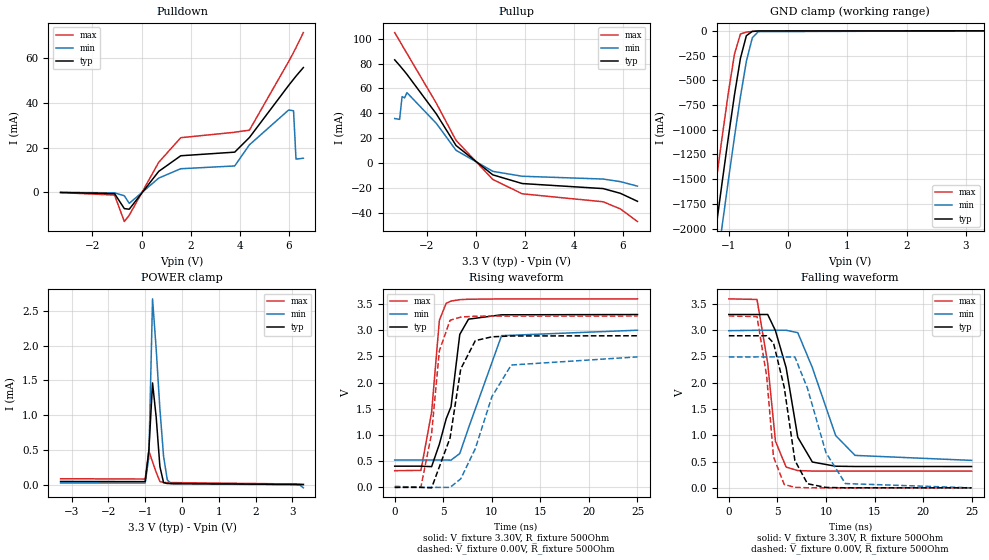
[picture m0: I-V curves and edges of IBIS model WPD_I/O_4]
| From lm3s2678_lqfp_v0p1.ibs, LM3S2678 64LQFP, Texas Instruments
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[Model]   WPD_I/O_4
Model_type   I/O
Vinl = 1.26
Vinh = 2.04
Vmeas = 1.65
| variable   typ   min   max
C_comp   9.739pF   9.739pF   9.803pF
[Model Spec]
Vinh+   1.91   1.78   2.04
Vinh-   1.90   1.76   2.03
Vinl+   1.40   1.27   1.54
Vinl-   1.39   1.26   1.53
| variable   typ   min   max
[Temperature Range]  25   85   -40
[Voltage Range]   3.3V   3.0V   3.6V
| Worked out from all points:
|   slope of the pulldown table from 0 to 0.495 V, typ, clamps not added: 71.6 ohm
|   slope of the pullup table from 0 to 0.495 V, typ, clamps not added: 71.6 ohm
|   GND clamp passes 1 mA (typ) near -0.48 V on its own axis
|   POWER clamp passes 1 mA (typ) near -0.71 V on its own axis
|   falling waveform, V_fixture 3.30V, R_fixture 500Ohm: 20-80 % time 1.98ns typ, 2.95ns min, 1.33ns max; typ from 3.3 V to 0.405 V
|   rising waveform, V_fixture 3.30V, R_fixture 500Ohm: 20-80 % time 1.71ns typ, 2.4ns min, 1.18ns max; typ from 0.405 V to 3.3 V
|   falling waveform, V_fixture 0.00V, R_fixture 500Ohm: 20-80 % time 1.7ns typ, 2.49ns min, 1.18ns max; typ from 2.89 V to 0 V
|   rising waveform, V_fixture 0.00V, R_fixture 500Ohm: 20-80 % time 2.03ns typ, 3.15ns min, 1.33ns max; typ from 0 V to 2.89 V
[Pulldown]
|  Voltage   I(typ)   I(min)   I(max)
-3.3V     -128.2uA   -72.79uA   -182.2uA
-1.1V     -636.2uA   -293.6uA   -1.283mA
-700mV    -7.354mA   -1.607mA   -13.15mA
-500mV    -7.623mA   -4.999mA   -10.32mA
700mV     9.301mA    6.299mA    13.36mA
1.6V      16.31mA    10.5mA     24.39mA
3.8V      17.93mA    11.75mA    26.84mA
4.4V      24.48mA    21.2mA     27.77mA
6V        47.8mA     36.79mA    58.49mA
6.2V      50.58mA    36.45mA    62.56mA
6.3V      51.96mA    14.82mA    64.7mA
6.6V      55.8mA     15.2mA     71.46mA
[Pullup]
|  Voltage   I(typ)   I(min)   I(max)
-3.3V     82.93mA    35.9mA     104.8mA
-3.1V     78.45mA    35.22mA    98.08mA
-3V       76.11mA    53.48mA    94.72mA
-2.9V     73.72mA    52.42mA    91.37mA
-2.8V     71.3mA     56.63mA    88.02mA
-1.6V     39.54mA    31.95mA    48.05mA
-800mV    14.3mA     10.46mA    18.4mA
700mV     -9.236mA   -6.432mA   -12.93mA
1.9V      -16.21mA   -10.36mA   -24.42mA
5.2V      -20.25mA   -12.6mA    -30.83mA
5.9V      -24.02mA   -14.69mA   -36.53mA
6.6V      -30.45mA   -18.28mA   -46.68mA
[GND Clamp]
|  Voltage   I(typ)   I(min)   I(max)
-3.3V     -11.73A    -12.14A    -11.32A
-1.4V     -2.85A     -3.29A     -2.391A
-1.3V     -2.393A    -2.835A    -1.933A
-1.2V     -1.942A    -2.383A    -1.481A
-1.1V     -1.496A    -1.937A    -1.038A
-1V       -1.061A    -1.498A    -612.1mA
-900mV    -646.5mA   -1.071A    -233.9mA
-800mV    -278.2mA   -665.9mA   -32.18mA
-700mV    -49.13mA   -307.7mA   -12.5mA
-600mV    -5.766mA   -70.86mA   -6.513mA
-500mV    -1.212mA   -8.171mA   -2.264mA
3.3V      16.11uA    11.95uA    29.77uA
[POWER Clamp]
|  Voltage   I(typ)   I(min)   I(max)
-3.3V     45.95uA    24.7uA     84.99uA
-1V       43.79uA    23.54uA    81.02uA
-900mV    497uA      400.5uA    481.3uA
-800mV    1.464mA    2.675mA    328uA
-700mV    965.7uA    1.944mA    175.8uA
-600mV    259.3uA    1.087mA    45.21uA
-500mV    29.01uA    407.8uA    31.06uA
-400mV    16.44uA    70.61uA    29.85uA
-300mV    16.12uA    11.95uA    29.79uA
3.1V      2.407uA    -925.9nA   9.193uA
3.2V      1.227uA    -4.064uA   7.471uA
3.3V      -117.9pA   -46.06uA   5.69uA
[Ramp]
| variable   typ   min   max
dV/dt_f   1.73/1.98n   1.48/2.95n   1.97/1.33n
dV/dt_r   1.74/2.03n   1.48/3.15n   1.96/1.33n
R_load = 500Ohm
[Falling Waveform]
V_fixture = 3.30V
V_fixture_min = 3.00V
V_fixture_max = 3.60V
R_fixture = 500Ohm
|   Time   V(typ)   V(min)   V(max)
0s        3.297V     2.99V      3.595V
2.9ns     3.297V     2.997V     3.584V
4ns       3.298V     2.998V     2.371V
4.8ns     2.99V      2.998V     887.6mV
5.9ns     2.286V     2.998V     394.2mV
7.1ns     961.8mV    2.952V     328.8mV
8.6ns     491.2mV    2.287V     319.7mV
11ns      411.2mV    995.1mV    318.6mV
13ns      406.3mV    617mV      318.5mV
25ns      405.4mV    522.4mV    318.5mV
[Rising Waveform]
V_fixture = 3.30V
V_fixture_min = 3.00V
V_fixture_max = 3.60V
R_fixture = 500Ohm
|   Time   V(typ)   V(min)   V(max)
0s        405.4mV    522.4mV    318.5mV
2.7ns     405.4mV    522.4mV    325.5mV
3.8ns     396.2mV    522.4mV    1.436V
4.6ns     825.6mV    522.4mV    3.19V
5.3ns     1.309V     522.4mV    3.512V
5.8ns     1.54V      520.4mV    3.555V
6.7ns     2.919V     646.8mV    3.582V
7.6ns     3.21V      1.134V     3.59V
11ns      3.293V     2.895V     3.596V
25ns      3.298V     2.999V     3.597V
[Falling Waveform]
V_fixture = 0.00V
V_fixture_min = 0.00V
V_fixture_max = 0.00V
R_fixture = 500Ohm
|   Time   V(typ)   V(min)   V(max)
0s        2.893V     2.49V      3.27V
2.9ns     2.893V     2.491V     3.258V
3.9ns     2.893V     2.491V     2.117V
4.6ns     2.755V     2.491V     588.5mV
5.7ns     1.917V     2.491V     64.29mV
6.8ns     521.4mV    2.49V      9.46mV
8.1ns     77.91mV    1.893V     1.44mV
10ns      7.517mV    669mV      209.9uV
12ns      1.014mV    81.45mV    73.19uV
25ns      18.39uV    38.9uV     11.44uV
[Rising Waveform]
V_fixture = 0.00V
V_fixture_min = 0.00V
V_fixture_max = 0.00V
R_fixture = 500Ohm
|   Time   V(typ)   V(min)   V(max)
0s        491.9uV    19.4mV     16.2uV
2.7ns     45.49uV    2.137mV    9.062mV
3.8ns     -8.433mV   973.8uV    1.029V
4.6ns     394.1mV    558.2uV    2.609V
5.7ns     943.7mV    269.7uV    3.188V
6.8ns     2.261V     163.8mV    3.25V
8.3ns     2.8V       740.2mV    3.266V
10ns      2.873V     1.728V     3.269V
12ns      2.889V     2.335V     3.269V
25ns      2.893V     2.49V      3.27V
